VERSION 5.7 ;
  NOWIREEXTENSIONATPIN ON ;
  DIVIDERCHAR "/" ;
  BUSBITCHARS "[]" ;
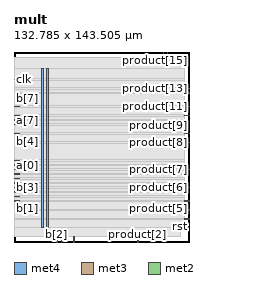
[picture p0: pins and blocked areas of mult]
MACRO mult
  CLASS BLOCK ;
  FOREIGN mult ;
  ORIGIN 0.000 0.000 ;
  SIZE 132.785 BY 143.505 ;
  PIN VGND
    DIRECTION INOUT ;
    USE GROUND ;
    PORT
      LAYER met4 ;
        RECT 24.340 10.640 25.940 130.800 ;
    END
  END VGND
  PIN VPWR
    DIRECTION INOUT ;
    USE POWER ;
    PORT
      LAYER met4 ;
        RECT 21.040 10.640 22.640 130.800 ;
    END
  END VPWR
  PIN a[0]
    DIRECTION INPUT ;
    USE SIGNAL ;
    ANTENNAGATEAREA 0.196500 ;
    PORT
      LAYER met3 ;
        RECT 0.000 57.840 4.000 58.440 ;
    END
  END a[0]
  PIN a[1]
    DIRECTION INPUT ;
    USE SIGNAL ;
    ANTENNAGATEAREA 0.196500 ;
    PORT
      LAYER met3 ;
        RECT 0.000 34.040 4.000 34.640 ;
    END
  END a[1]
  PIN a[2]
    DIRECTION INPUT ;
    USE SIGNAL ;
    ANTENNAGATEAREA 0.196500 ;
    PORT
      LAYER met3 ;
        RECT 0.000 44.240 4.000 44.840 ;
    END
  END a[2]
  PIN a[3]
    DIRECTION INPUT ;
    USE SIGNAL ;
    ANTENNAGATEAREA 0.196500 ;
    PORT
      LAYER met3 ;
        RECT 0.000 37.440 4.000 38.040 ;
    END
  END a[3]
  PIN a[4]
    DIRECTION INPUT ;
    USE SIGNAL ;
    ANTENNAGATEAREA 0.196500 ;
    PORT
      LAYER met3 ;
        RECT 0.000 61.240 4.000 61.840 ;
    END
  END a[4]
  PIN a[5]
    DIRECTION INPUT ;
    USE SIGNAL ;
    ANTENNAGATEAREA 0.196500 ;
    PORT
      LAYER met3 ;
        RECT 0.000 54.440 4.000 55.040 ;
    END
  END a[5]
  PIN a[6]
    DIRECTION INPUT ;
    USE SIGNAL ;
    ANTENNAGATEAREA 0.196500 ;
    PORT
      LAYER met3 ;
        RECT 0.000 95.240 4.000 95.840 ;
    END
  END a[6]
  PIN a[7]
    DIRECTION INPUT ;
    USE SIGNAL ;
    ANTENNAGATEAREA 0.196500 ;
    PORT
      LAYER met3 ;
        RECT 0.000 91.840 4.000 92.440 ;
    END
  END a[7]
  PIN b[0]
    DIRECTION INPUT ;
    USE SIGNAL ;
    ANTENNAGATEAREA 0.196500 ;
    PORT
      LAYER met3 ;
        RECT 0.000 47.640 4.000 48.240 ;
    END
  END b[0]
  PIN b[1]
    DIRECTION INPUT ;
    USE SIGNAL ;
    ANTENNAGATEAREA 0.196500 ;
    PORT
      LAYER met3 ;
        RECT 0.000 30.640 4.000 31.240 ;
    END
  END b[1]
  PIN b[2]
    DIRECTION INPUT ;
    USE SIGNAL ;
    ANTENNAGATEAREA 0.196500 ;
    PORT
      LAYER met2 ;
        RECT 32.290 0.000 32.570 4.000 ;
    END
  END b[2]
  PIN b[3]
    DIRECTION INPUT ;
    USE SIGNAL ;
    ANTENNAGATEAREA 0.196500 ;
    PORT
      LAYER met3 ;
        RECT 0.000 40.840 4.000 41.440 ;
    END
  END b[3]
  PIN b[4]
    DIRECTION INPUT ;
    USE SIGNAL ;
    ANTENNAGATEAREA 0.196500 ;
    PORT
      LAYER met3 ;
        RECT 0.000 81.640 4.000 82.240 ;
    END
  END b[4]
  PIN b[5]
    DIRECTION INPUT ;
    USE SIGNAL ;
    ANTENNAGATEAREA 0.196500 ;
    PORT
      LAYER met3 ;
        RECT 0.000 51.040 4.000 51.640 ;
    END
  END b[5]
  PIN b[6]
    DIRECTION INPUT ;
    USE SIGNAL ;
    ANTENNAGATEAREA 0.196500 ;
    PORT
      LAYER met3 ;
        RECT 0.000 88.440 4.000 89.040 ;
    END
  END b[6]
  PIN b[7]
    DIRECTION INPUT ;
    USE SIGNAL ;
    ANTENNAGATEAREA 0.196500 ;
    PORT
      LAYER met3 ;
        RECT 0.000 102.040 4.000 102.640 ;
    END
  END b[7]
  PIN clk
    DIRECTION INPUT ;
    USE SIGNAL ;
    ANTENNAGATEAREA 0.852000 ;
    PORT
      LAYER met3 ;
        RECT 0.000 122.440 4.000 123.040 ;
    END
  END clk
  PIN product[0]
    DIRECTION OUTPUT ;
    USE SIGNAL ;
    ANTENNADIFFAREA 0.445500 ;
    PORT
      LAYER met2 ;
        RECT 45.170 0.000 45.450 4.000 ;
    END
  END product[0]
  PIN product[10]
    DIRECTION OUTPUT ;
    USE SIGNAL ;
    ANTENNADIFFAREA 0.445500 ;
    PORT
      LAYER met3 ;
        RECT 128.785 95.240 132.785 95.840 ;
    END
  END product[10]
  PIN product[11]
    DIRECTION OUTPUT ;
    USE SIGNAL ;
    ANTENNADIFFAREA 0.445500 ;
    PORT
      LAYER met3 ;
        RECT 128.785 102.040 132.785 102.640 ;
    END
  END product[11]
  PIN product[12]
    DIRECTION OUTPUT ;
    USE SIGNAL ;
    ANTENNADIFFAREA 0.445500 ;
    PORT
      LAYER met3 ;
        RECT 128.785 112.240 132.785 112.840 ;
    END
  END product[12]
  PIN product[13]
    DIRECTION OUTPUT ;
    USE SIGNAL ;
    ANTENNADIFFAREA 0.445500 ;
    PORT
      LAYER met3 ;
        RECT 128.785 115.640 132.785 116.240 ;
    END
  END product[13]
  PIN product[14]
    DIRECTION OUTPUT ;
    USE SIGNAL ;
    ANTENNADIFFAREA 0.445500 ;
    PORT
      LAYER met2 ;
        RECT 116.010 139.505 116.290 143.505 ;
    END
  END product[14]
  PIN product[15]
    DIRECTION OUTPUT ;
    USE SIGNAL ;
    ANTENNADIFFAREA 0.445500 ;
    PORT
      LAYER met2 ;
        RECT 112.790 139.505 113.070 143.505 ;
    END
  END product[15]
  PIN product[1]
    DIRECTION OUTPUT ;
    USE SIGNAL ;
    ANTENNADIFFAREA 0.445500 ;
    PORT
      LAYER met2 ;
        RECT 35.510 0.000 35.790 4.000 ;
    END
  END product[1]
  PIN product[2]
    DIRECTION OUTPUT ;
    USE SIGNAL ;
    ANTENNADIFFAREA 0.445500 ;
    PORT
      LAYER met2 ;
        RECT 93.470 0.000 93.750 4.000 ;
    END
  END product[2]
  PIN product[3]
    DIRECTION OUTPUT ;
    USE SIGNAL ;
    ANTENNADIFFAREA 0.445500 ;
    PORT
      LAYER met2 ;
        RECT 103.130 0.000 103.410 4.000 ;
    END
  END product[3]
  PIN product[4]
    DIRECTION OUTPUT ;
    USE SIGNAL ;
    ANTENNADIFFAREA 0.445500 ;
    PORT
      LAYER met3 ;
        RECT 128.785 23.840 132.785 24.440 ;
    END
  END product[4]
  PIN product[5]
    DIRECTION OUTPUT ;
    USE SIGNAL ;
    ANTENNADIFFAREA 0.445500 ;
    PORT
      LAYER met3 ;
        RECT 128.785 30.640 132.785 31.240 ;
    END
  END product[5]
  PIN product[6]
    DIRECTION OUTPUT ;
    USE SIGNAL ;
    ANTENNADIFFAREA 0.445500 ;
    PORT
      LAYER met3 ;
        RECT 128.785 40.840 132.785 41.440 ;
    END
  END product[6]
  PIN product[7]
    DIRECTION OUTPUT ;
    USE SIGNAL ;
    ANTENNADIFFAREA 0.445500 ;
    PORT
      LAYER met3 ;
        RECT 128.785 54.440 132.785 55.040 ;
    END
  END product[7]
  PIN product[8]
    DIRECTION OUTPUT ;
    USE SIGNAL ;
    ANTENNADIFFAREA 0.445500 ;
    PORT
      LAYER met3 ;
        RECT 128.785 74.840 132.785 75.440 ;
    END
  END product[8]
  PIN product[9]
    DIRECTION OUTPUT ;
    USE SIGNAL ;
    ANTENNADIFFAREA 0.445500 ;
    PORT
      LAYER met3 ;
        RECT 128.785 81.640 132.785 82.240 ;
    END
  END product[9]
  PIN rst
    DIRECTION INPUT ;
    USE SIGNAL ;
    ANTENNAGATEAREA 0.196500 ;
    PORT
      LAYER met3 ;
        RECT 128.785 17.040 132.785 17.640 ;
    END
  END rst
  OBS
      LAYER nwell ;
        RECT 5.330 10.795 127.150 130.645 ;
      LAYER li1 ;
        RECT 5.520 10.795 126.960 130.645 ;
      LAYER met1 ;
        RECT 0.530 10.640 126.960 130.800 ;
      LAYER met2 ;
        RECT 0.550 139.225 112.510 139.505 ;
        RECT 113.350 139.225 115.730 139.505 ;
        RECT 116.570 139.225 125.490 139.505 ;
        RECT 0.550 4.280 125.490 139.225 ;
        RECT 0.550 4.000 32.010 4.280 ;
        RECT 32.850 4.000 35.230 4.280 ;
        RECT 36.070 4.000 44.890 4.280 ;
        RECT 45.730 4.000 93.190 4.280 ;
        RECT 94.030 4.000 102.850 4.280 ;
        RECT 103.690 4.000 125.490 4.280 ;
      LAYER met3 ;
        RECT 0.525 123.440 128.785 130.725 ;
        RECT 4.400 122.040 128.785 123.440 ;
        RECT 0.525 116.640 128.785 122.040 ;
        RECT 0.525 115.240 128.385 116.640 ;
        RECT 0.525 113.240 128.785 115.240 ;
        RECT 0.525 111.840 128.385 113.240 ;
        RECT 0.525 103.040 128.785 111.840 ;
        RECT 4.400 101.640 128.385 103.040 ;
        RECT 0.525 96.240 128.785 101.640 ;
        RECT 4.400 94.840 128.385 96.240 ;
        RECT 0.525 92.840 128.785 94.840 ;
        RECT 4.400 91.440 128.785 92.840 ;
        RECT 0.525 89.440 128.785 91.440 ;
        RECT 4.400 88.040 128.785 89.440 ;
        RECT 0.525 82.640 128.785 88.040 ;
        RECT 4.400 81.240 128.385 82.640 ;
        RECT 0.525 75.840 128.785 81.240 ;
        RECT 0.525 74.440 128.385 75.840 ;
        RECT 0.525 62.240 128.785 74.440 ;
        RECT 4.400 60.840 128.785 62.240 ;
        RECT 0.525 58.840 128.785 60.840 ;
        RECT 4.400 57.440 128.785 58.840 ;
        RECT 0.525 55.440 128.785 57.440 ;
        RECT 4.400 54.040 128.385 55.440 ;
        RECT 0.525 52.040 128.785 54.040 ;
        RECT 4.400 50.640 128.785 52.040 ;
        RECT 0.525 48.640 128.785 50.640 ;
        RECT 4.400 47.240 128.785 48.640 ;
        RECT 0.525 45.240 128.785 47.240 ;
        RECT 4.400 43.840 128.785 45.240 ;
        RECT 0.525 41.840 128.785 43.840 ;
        RECT 4.400 40.440 128.385 41.840 ;
        RECT 0.525 38.440 128.785 40.440 ;
        RECT 4.400 37.040 128.785 38.440 ;
        RECT 0.525 35.040 128.785 37.040 ;
        RECT 4.400 33.640 128.785 35.040 ;
        RECT 0.525 31.640 128.785 33.640 ;
        RECT 4.400 30.240 128.385 31.640 ;
        RECT 0.525 24.840 128.785 30.240 ;
        RECT 0.525 23.440 128.385 24.840 ;
        RECT 0.525 18.040 128.785 23.440 ;
        RECT 0.525 16.640 128.385 18.040 ;
        RECT 0.525 10.715 128.785 16.640 ;
  END
END mult
END LIBRARY

